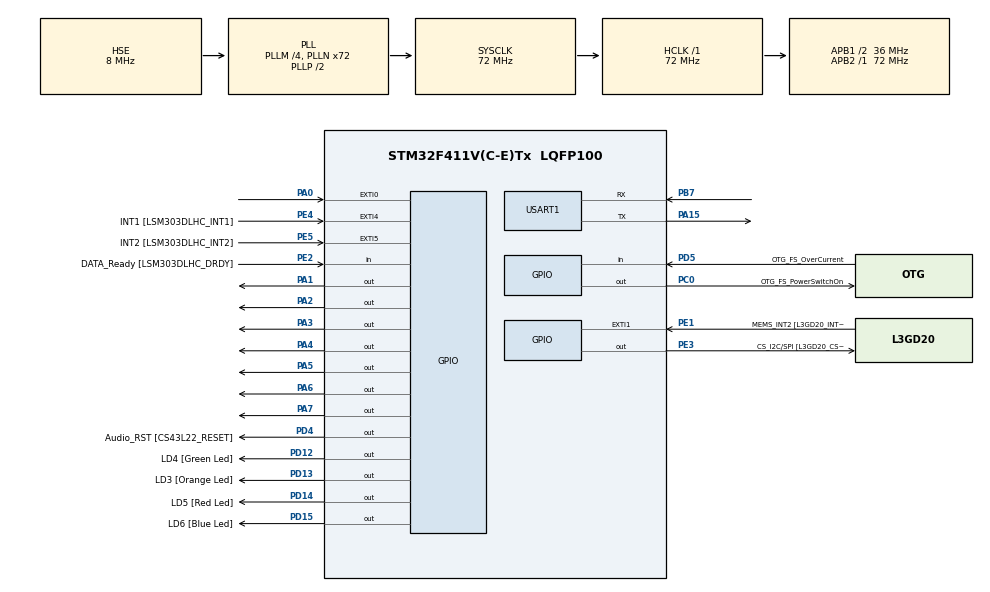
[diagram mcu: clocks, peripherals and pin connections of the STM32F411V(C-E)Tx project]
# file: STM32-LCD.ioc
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Mcu.Family=STM32F4
Mcu.Name=STM32F411V(C-E)Tx
Mcu.Package=LQFP100
NVIC.PriorityGroup=NVIC_PRIORITYGROUP_0
PA0-WKUP.GPIO_ModeDefaultEXTI=GPIO_MODE_EVT_RISING
PA0-WKUP.Signal=GPXTI0
PA1.Signal=GPIO_Output
PA10.GPIO_Label=OTG_FS_ID
PA10.Signal=USB_OTG_FS_ID
PA11.GPIO_Label=OTG_FS_DM
PA11.Signal=USB_OTG_FS_DM
PA12.GPIO_Label=OTG_FS_DP
PA12.Signal=USB_OTG_FS_DP
PA13.GPIO_Label=SWDIO
PA13.Mode=Serial_Wire
PA13.Signal=SYS_JTMS-SWDIO
PA14.GPIO_Label=SWCLK
PA14.Mode=Serial_Wire
PA14.Signal=SYS_JTCK-SWCLK
PA15.Mode=Asynchronous
PA15.Signal=USART1_TX
PA2.Signal=GPIO_Output
PA3.Signal=GPIO_Output
PA4.Signal=GPIO_Output
PA5.Signal=GPIO_Output
PA6.Signal=GPIO_Output
PA7.Signal=GPIO_Output
PA9.GPIO_Label=VBUS_FS
PA9.Signal=USB_OTG_FS_VBUS
PB10.GPIO_Label=CLK_IN [MP45DT02_CLK]
PB10.Signal=I2S2_CK
PB12.Signal=I2S2_WS
PB3.GPIO_Label=SWO
PB3.Signal=SYS_JTDO-SWO
PB6.GPIO_Label=Audio_SCL [CS43L22_SCL]
PB6.GPIO_Mode=GPIO_MODE_AF_OD
PB6.GPIO_Pu=GPIO_PULLUP
PB6.GPIO_PuPd=GPIO_NOPULL
PB6.GPIO_Speed=GPIO_SPEED_FREQ_LOW
PB6.Signal=I2C1_SCL
PB7.Mode=Asynchronous
PB7.Signal=USART1_RX
PB9.GPIO_Label=Audio_SDA [CS43L22_SDA]
PB9.GPIO_Mode=GPIO_MODE_AF_OD
PB9.GPIO_Pu=GPIO_PULLUP
PB9.GPIO_PuPd=GPIO_NOPULL
PB9.GPIO_Speed=GPIO_SPEED_FREQ_LOW
PB9.Signal=I2C1_SDA
PC0.GPIO_Label=OTG_FS_PowerSwitchOn
PC0.PinState=GPIO_PIN_SET
PC0.Signal=GPIO_Output
PC10.GPIO_Label=I2S3_SCK [CS43L22_SCLK]
PC10.GPIO_Mode=GPIO_MODE_AF_PP
PC10.GPIO_PuPd=GPIO_NOPULL
PC10.GPIO_Speed=GPIO_SPEED_FREQ_LOW
PC10.Signal=I2S3_CK
PC12.GPIO_Label=I2S3_SD [CS43L22_SDIN]
PC12.GPIO_Mode=GPIO_MODE_AF_PP
PC12.GPIO_PuPd=GPIO_NOPULL
PC12.GPIO_Speed=GPIO_SPEED_FREQ_LOW
PC12.Signal=I2S3_SD
PC14-OSC32_IN.GPIO_Label=PC14-OSC32_IN
PC14-OSC32_IN.Mode=LSE-External-Oscillator
PC14-OSC32_IN.Signal=RCC_OSC32_IN
PC15-OSC32_OUT.GPIO_Label=PC15-OSC32_OUT
PC15-OSC32_OUT.Mode=LSE-External-Oscillator
PC15-OSC32_OUT.Signal=RCC_OSC32_OUT
PC3.GPIO_Label=PDM_OUT [MP45DT02_DOUT]
PC3.Signal=I2S2_SD
PC7.GPIO_Label=I2S3_MCK [CS43L22_MCLK]
PC7.GPIO_Mode=GPIO_MODE_AF_PP
PC7.GPIO_PuPd=GPIO_NOPULL
PC7.GPIO_Speed=GPIO_SPEED_FREQ_LOW
PC7.Signal=I2S3_MCK
PD12.GPIO_Label=LD4 [Green Led]
PD12.GPIO_PuPd=GPIO_NOPULL
PD12.GPIO_Speed=GPIO_SPEED_FREQ_LOW
PD12.Signal=GPIO_Output
PD13.GPIO_Label=LD3 [Orange Led]
PD13.GPIO_PuPd=GPIO_NOPULL
PD13.GPIO_Speed=GPIO_SPEED_FREQ_LOW
PD13.Signal=GPIO_Output
PD14.GPIO_Label=LD5 [Red Led]
PD14.GPIO_PuPd=GPIO_NOPULL
PD14.GPIO_Speed=GPIO_SPEED_FREQ_LOW
PD14.Signal=GPIO_Output
PD15.GPIO_Label=LD6 [Blue Led]
PD15.GPIO_PuPd=GPIO_NOPULL
PD15.GPIO_Speed=GPIO_SPEED_FREQ_LOW
PD15.Signal=GPIO_Output
PD4.GPIO_Label=Audio_RST [CS43L22_RESET]
PD4.Signal=GPIO_Output
PD5.GPIO_Label=OTG_FS_OverCurrent
PD5.Signal=GPIO_Input
PE1.GPIO_Label=MEMS_INT2 [L3GD20_INT2]
PE1.GPIO_ModeDefaultEXTI=GPIO_MODE_EVT_RISING
PE1.Signal=GPXTI1
PE2.GPIO_Label=DATA_Ready [LSM303DLHC_DRDY]
PE2.Signal=GPIO_Input
PE3.GPIO_Label=CS_I2C/SPI [L3GD20_CS_I2C/SPI]
PE3.Signal=GPIO_Output
PE4.GPIO_Label=INT1 [LSM303DLHC_INT1]
PE4.GPIO_ModeDefaultEXTI=GPIO_MODE_EVT_RISING
PE4.Signal=GPXTI4
PE5.GPIO_Label=INT2 [LSM303DLHC_INT2]
PE5.GPIO_ModeDefaultEXTI=GPIO_MODE_EVT_RISING
PE5.Signal=GPXTI5
PH0\ -\ OSC_IN.GPIO_Label=PH0-OSC_IN
PH0\ -\ OSC_IN.Mode=HSE-External-Oscillator
PH0\ -\ OSC_IN.Signal=RCC_OSC_IN
PH1\ -\ OSC_OUT.GPIO_Label=PH1-OSC_OUT
PH1\ -\ OSC_OUT.Mode=HSE-External-Oscillator
PH1\ -\ OSC_OUT.Signal=RCC_OSC_OUT
ProjectManager.HeapSize=0x200
ProjectManager.StackSize=0x400
ProjectManager.TargetToolchain=STM32CubeIDE
RCC.48MHZClocksFreq_Value=48000000
RCC.AHBFreq_Value=72000000
RCC.APB1CLKDivider=RCC_HCLK_DIV2
RCC.APB1Freq_Value=36000000
RCC.APB1TimFreq_Value=72000000
RCC.APB2Freq_Value=72000000
RCC.APB2TimFreq_Value=72000000
RCC.CortexFreq_Value=72000000
RCC.HCLKFreq_Value=72000000
RCC.HSE_VALUE=8000000
RCC.HSI_VALUE=16000000
RCC.PLLI2SM=5
RCC.PLLI2SN=200
RCC.PLLM=4
RCC.PLLN=72
RCC.PLLQ=3
RCC.PLLSourceVirtual=RCC_PLLSOURCE_HSE
RCC.SYSCLKFreq_VALUE=72000000
RCC.SYSCLKSource=RCC_SYSCLKSOURCE_PLLCLK
RCC.VCOOutputFreq_Value=144000000
TIM1.Period=0xFFFF-1
TIM1.Prescaler=72-1
USART1.VirtualMode=VM_ASYNC
VP_TIM1_VS_ClockSourceINT.Mode=Internal
board=STM32F411E-DISCO

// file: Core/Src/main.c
/* USER CODE BEGIN Header */
/**
  ******************************************************************************
  * @file           : main.c
  * @brief          : Main program body
  ******************************************************************************
  * @attention
  *
  * Copyright (c) 2022 STMicroelectronics.
  * All rights reserved.
  *
  * This software is licensed under terms that can be found in the LICENSE file
  * in the root directory of this software component.
  * If no LICENSE file comes with this software, it is provided AS-IS.
  *
  ******************************************************************************
  */
/* USER CODE END Header */
#include "main.h"

/* USER CODE BEGIN Includes */
#include "LCD1602.h"
/* USER CODE END Includes */

TIM_HandleTypeDef htim1;

UART_HandleTypeDef huart1;

void SystemClock_Config(void);
static void MX_GPIO_Init(void);
static void MX_TIM1_Init(void);
static void MX_USART1_UART_Init(void);

/* USER CODE BEGIN 0 */
int row=0;
int col=0;
/* USER CODE END 0 */

int main(void)
{

  /* MCU Configuration--------------------------------------------------------*/

  /* Reset of all peripherals, Initializes the Flash interface and the Systick. */
  HAL_Init();

  /* Configure the system clock */
  SystemClock_Config();

  /* Initialize all configured peripherals */
  MX_GPIO_Init();
  MX_TIM1_Init();
  MX_USART1_UART_Init();
  /* USER CODE BEGIN 2 */
  HAL_TIM_Base_Start(&htim1);

  lcd_init ();
  lcd_clear();
  lcd_put_cur(0, 0);
  lcd_send_string("HELLO ");
  lcd_send_string("WORLD ");
  lcd_send_string("FROM");

  lcd_put_cur(1, 0);
  lcd_send_string("Shuran & Ritika");
  HAL_Delay(3000);
  lcd_clear();

  /* USER CODE END 2 */

  /* Infinite loop */
  while (1)
  {

    /* USER CODE BEGIN 3 */

	  for (int i=0;i<128;i++)
	  {
		  lcd_put_cur(row, col);

		  lcd_send_data(i+48);

		  col++;

		  if (col > 15) {row++; col = 0;}
		  if (row > 1) row=0;

		  HAL_Delay(250);
	  }

  }

  /* USER CODE END 3 */
}

void SystemClock_Config(void)
{
  RCC_OscInitTypeDef RCC_OscInitStruct = {0};
  RCC_ClkInitTypeDef RCC_ClkInitStruct = {0};

  /** Configure the main internal regulator output voltage
  */
  __HAL_RCC_PWR_CLK_ENABLE();
  __HAL_PWR_VOLTAGESCALING_CONFIG(PWR_REGULATOR_VOLTAGE_SCALE1);

  /** Initializes the RCC Oscillators according to the specified parameters
  * in the RCC_OscInitTypeDef structure.
  */
  RCC_OscInitStruct.OscillatorType = RCC_OSCILLATORTYPE_HSE;
  RCC_OscInitStruct.HSEState = RCC_HSE_ON;
  RCC_OscInitStruct.PLL.PLLState = RCC_PLL_ON;
  RCC_OscInitStruct.PLL.PLLSource = RCC_PLLSOURCE_HSE;
  RCC_OscInitStruct.PLL.PLLM = 4;
  RCC_OscInitStruct.PLL.PLLN = 72;
  RCC_OscInitStruct.PLL.PLLP = RCC_PLLP_DIV2;
  RCC_OscInitStruct.PLL.PLLQ = 3;
  if (HAL_RCC_OscConfig(&RCC_OscInitStruct) != HAL_OK)
  {
    Error_Handler();
  }

  /** Initializes the CPU, AHB and APB buses clocks
  */
  RCC_ClkInitStruct.ClockType = RCC_CLOCKTYPE_HCLK|RCC_CLOCKTYPE_SYSCLK
                              |RCC_CLOCKTYPE_PCLK1|RCC_CLOCKTYPE_PCLK2;
  RCC_ClkInitStruct.SYSCLKSource = RCC_SYSCLKSOURCE_PLLCLK;
  RCC_ClkInitStruct.AHBCLKDivider = RCC_SYSCLK_DIV1;
  RCC_ClkInitStruct.APB1CLKDivider = RCC_HCLK_DIV2;
  RCC_ClkInitStruct.APB2CLKDivider = RCC_HCLK_DIV1;

  if (HAL_RCC_ClockConfig(&RCC_ClkInitStruct, FLASH_LATENCY_2) != HAL_OK)
  {
    Error_Handler();
  }
}

static void MX_TIM1_Init(void)
{

  TIM_ClockConfigTypeDef sClockSourceConfig = {0};
  TIM_MasterConfigTypeDef sMasterConfig = {0};

  htim1.Instance = TIM1;
  htim1.Init.Prescaler = 72-1;
  htim1.Init.CounterMode = TIM_COUNTERMODE_UP;
  htim1.Init.Period = 0xFFFF-1;
  htim1.Init.ClockDivision = TIM_CLOCKDIVISION_DIV1;
  htim1.Init.RepetitionCounter = 0;
  htim1.Init.AutoReloadPreload = TIM_AUTORELOAD_PRELOAD_DISABLE;
  if (HAL_TIM_Base_Init(&htim1) != HAL_OK)
  {
    Error_Handler();
  }
  sClockSourceConfig.ClockSource = TIM_CLOCKSOURCE_INTERNAL;
  if (HAL_TIM_ConfigClockSource(&htim1, &sClockSourceConfig) != HAL_OK)
  {
    Error_Handler();
  }
  sMasterConfig.MasterOutputTrigger = TIM_TRGO_RESET;
  sMasterConfig.MasterSlaveMode = TIM_MASTERSLAVEMODE_DISABLE;
  if (HAL_TIMEx_MasterConfigSynchronization(&htim1, &sMasterConfig) != HAL_OK)
  {
    Error_Handler();
  }

}

static void MX_USART1_UART_Init(void)
{

  huart1.Instance = USART1;
  huart1.Init.BaudRate = 115200;
  huart1.Init.WordLength = UART_WORDLENGTH_8B;
  huart1.Init.StopBits = UART_STOPBITS_1;
  huart1.Init.Parity = UART_PARITY_NONE;
  huart1.Init.Mode = UART_MODE_TX_RX;
  huart1.Init.HwFlowCtl = UART_HWCONTROL_NONE;
  huart1.Init.OverSampling = UART_OVERSAMPLING_16;
  if (HAL_UART_Init(&huart1) != HAL_OK)
  {
    Error_Handler();
  }

}

static void MX_GPIO_Init(void)
{
  GPIO_InitTypeDef GPIO_InitStruct = {0};

  /* GPIO Ports Clock Enable */
  __HAL_RCC_GPIOD_CLK_ENABLE();
  __HAL_RCC_GPIOA_CLK_ENABLE();
  __HAL_RCC_GPIOB_CLK_ENABLE();
  __HAL_RCC_GPIOC_CLK_ENABLE();

  /*Configure GPIO pin Output Level */
  HAL_GPIO_WritePin(GPIOD, GPIO_PIN_1|GPIO_PIN_2|GPIO_PIN_3|GPIO_PIN_4
                          |GPIO_PIN_5|GPIO_PIN_6|GPIO_PIN_7, GPIO_PIN_RESET);

  /*Configure GPIO pins : PA1 PA2 PA3 PA4
                           PA5 PA6 PA7 */
  GPIO_InitStruct.Pin = GPIO_PIN_1|GPIO_PIN_2|GPIO_PIN_3|GPIO_PIN_4
                          |GPIO_PIN_5|GPIO_PIN_6|GPIO_PIN_7;
  GPIO_InitStruct.Mode = GPIO_MODE_OUTPUT_PP;
  GPIO_InitStruct.Pull = GPIO_NOPULL;
  GPIO_InitStruct.Speed = GPIO_SPEED_FREQ_LOW;
  HAL_GPIO_Init(GPIOD, &GPIO_InitStruct);

}

/* USER CODE BEGIN 4 */
#ifdef __GNUC__
  /* With GCC, small printf (option LD Linker->Libraries->Small printf
     set to 'Yes') calls __io_putchar() */
int __io_putchar(int ch)
#else
int fputc(int ch, FILE *f)
#endif /* __GNUC__ */
{
  /* Place your implementation of fputc here */
  /* e.g. write a character to the UART3 and Loop until the end of transmission */
  HAL_UART_Transmit(&huart1, (uint8_t *)&ch, 1, HAL_MAX_DELAY);
  return ch;
}
/* USER CODE END 4 */

void Error_Handler(void)
{
  __disable_irq();
  while (1)
  {
  }
}
